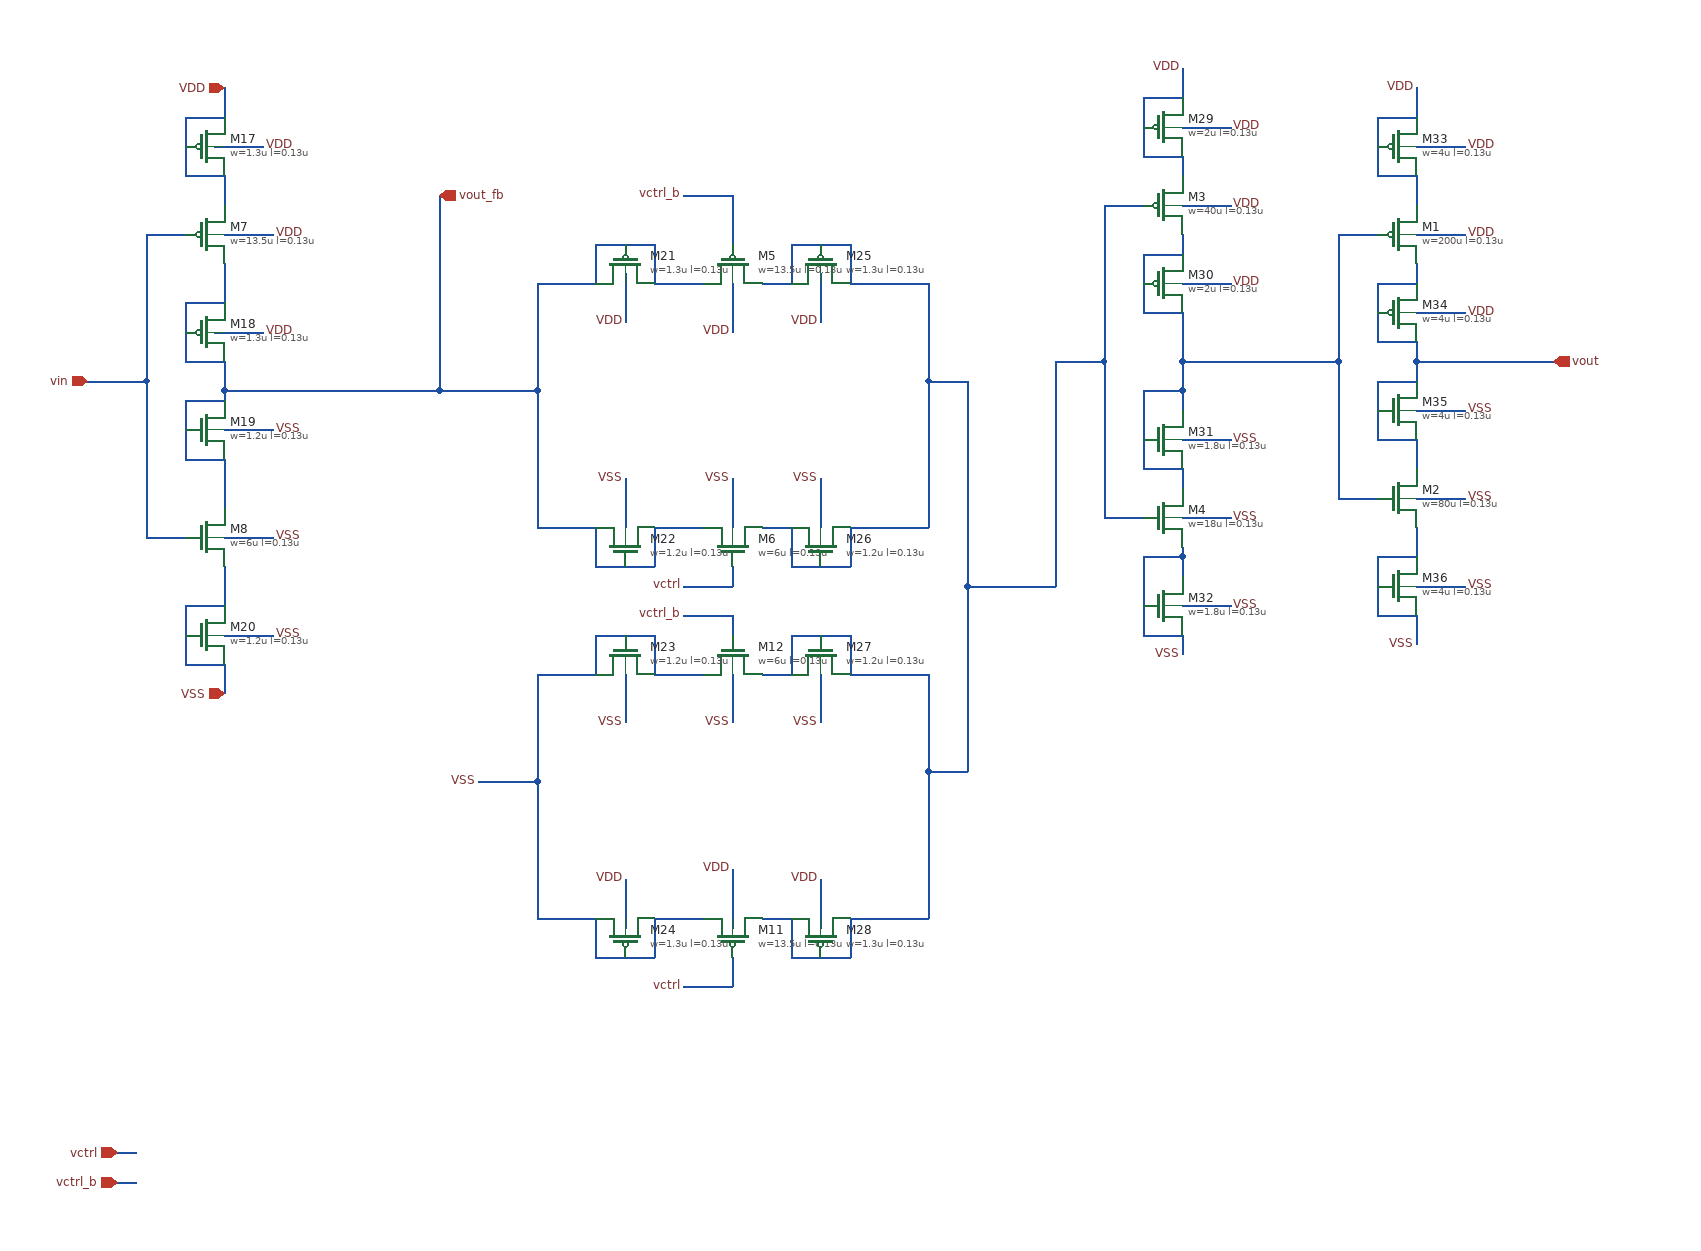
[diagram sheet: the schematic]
v {xschem version=3.4.8RC file_version=1.3}
G {}
K {}
V {}
S {}
F {}
E {}
N 510 -1400 550 -1400 {lab=vin}
N 510 -1090 550 -1090 {lab=vin}
N 590 -1460 590 -1430 {lab=VDD}
N 590 -960 590 -930 {lab=VSS}
N 590 -1400 640 -1400 {lab=VDD}
N 590 -1090 640 -1090 {lab=VSS}
N 510 -1400 510 -1250 {lab=vin}
N 1490 -1430 1530 -1430 {lab=#net1}
N 1490 -1110 1530 -1110 {lab=#net1}
N 1570 -1570 1570 -1540 {lab=VDD}
N 1570 -1070 1570 -1050 {lab=VSS}
N 1570 -1430 1620 -1430 {lab=VDD}
N 1570 -1110 1620 -1110 {lab=VSS}
N 1730 -1400 1770 -1400 {lab=#net2}
N 1730 -1130 1770 -1130 {lab=#net2}
N 1810 -1460 1810 -1430 {lab=VDD}
N 1810 -1100 1810 -1070 {lab=VSS}
N 1810 -1400 1860 -1400 {lab=VDD}
N 1810 -1130 1860 -1130 {lab=VSS}
N 1810 -1270 1810 -1250 {lab=vout}
N 1810 -1270 1950 -1270 {lab=vout}
N 1810 -1290 1810 -1270 {lab=vout}
N 450 -1250 510 -1250 {lab=vin}
N 1570 -1160 1570 -1140 {lab=#net2}
N 1570 -1270 1730 -1270 {lab=#net2}
N 1730 -1270 1730 -1130 {lab=#net2}
N 590 -1370 590 -1330 {lab=vout_fb}
N 1110 -1150 1110 -1100 {lab=VSS}
N 1110 -1350 1110 -1300 {lab=VDD}
N 1110 -1440 1110 -1390 {lab=vctrl_b}
N 1060 -1440 1110 -1440 {lab=vctrl_b}
N 910 -950 970 -950 {lab=VSS}
N 1110 -950 1110 -900 {lab=VSS}
N 1060 -1010 1110 -1010 {lab=vctrl_b}
N 1110 -1010 1110 -990 {lab=vctrl_b}
N 1060 -630 1110 -630 {lab=vctrl}
N 850 -840 910 -840 {lab=VSS}
N 910 -950 910 -840 {lab=VSS}
N 1310 -850 1350 -850 {lab=#net1}
N 1310 -950 1310 -850 {lab=#net1}
N 1350 -1040 1350 -850 {lab=#net1}
N 1310 -1250 1350 -1250 {lab=#net1}
N 1310 -1350 1310 -1250 {lab=#net1}
N 910 -1240 910 -1100 {lab=vout_fb}
N 1350 -1040 1440 -1040 {lab=#net1}
N 1350 -1250 1350 -1040 {lab=#net1}
N 1440 -1270 1440 -1040 {lab=#net1}
N 1440 -1270 1490 -1270 {lab=#net1}
N 810 -1240 910 -1240 {lab=vout_fb}
N 480 -460 500 -460 {lab=vctrl}
N 810 -1440 810 -1240 {lab=vout_fb}
N 580 -1490 630 -1490 {lab=VDD}
N 550 -1460 590 -1460 {lab=VDD}
N 550 -1520 550 -1460 {lab=VDD}
N 550 -1520 590 -1520 {lab=VDD}
N 590 -1550 590 -1520 {lab=VDD}
N 580 -1300 630 -1300 {lab=VDD}
N 550 -1270 590 -1270 {lab=vout_fb}
N 550 -1330 550 -1270 {lab=vout_fb}
N 550 -1330 590 -1330 {lab=vout_fb}
N 550 -1170 590 -1170 {lab=vout_fb}
N 550 -1230 550 -1170 {lab=vout_fb}
N 550 -1230 590 -1230 {lab=vout_fb}
N 590 -1200 640 -1200 {lab=VSS}
N 590 -1240 590 -1230 {lab=vout_fb}
N 550 -960 590 -960 {lab=VSS}
N 550 -1020 550 -960 {lab=VSS}
N 550 -1020 590 -1020 {lab=VSS}
N 590 -990 640 -990 {lab=VSS}
N 590 -1060 590 -1020 {lab=VSS}
N 510 -1250 510 -1090 {lab=vin}
N 590 -1240 810 -1240 {lab=vout_fb}
N 590 -1270 590 -1240 {lab=vout_fb}
N 910 -1350 910 -1240 {lab=vout_fb}
N 1000 -1360 1000 -1310 {lab=VDD}
N 970 -1390 970 -1350 {lab=vout_fb}
N 970 -1390 1030 -1390 {lab=vout_fb}
N 1030 -1390 1030 -1350 {lab=vout_fb}
N 1030 -1350 1080 -1350 {lab=vout_fb}
N 910 -1350 970 -1350 {lab=vout_fb}
N 970 -1100 970 -1060 {lab=vout_fb}
N 970 -1060 1030 -1060 {lab=vout_fb}
N 1030 -1100 1030 -1060 {lab=vout_fb}
N 1060 -1040 1110 -1040 {lab=vctrl}
N 1110 -1060 1110 -1040 {lab=vctrl}
N 1310 -1250 1310 -1100 {lab=#net1}
N 1030 -1100 1080 -1100 {lab=vout_fb}
N 910 -1100 970 -1100 {lab=vout_fb}
N 1000 -1150 1000 -1100 {lab=VSS}
N 970 -990 970 -950 {lab=VSS}
N 970 -990 1030 -990 {lab=VSS}
N 1030 -990 1030 -950 {lab=VSS}
N 1000 -950 1000 -900 {lab=VSS}
N 1030 -950 1080 -950 {lab=VSS}
N 1000 -740 1000 -690 {lab=VDD}
N 1030 -700 1030 -660 {lab=VSS}
N 970 -660 1030 -660 {lab=VSS}
N 970 -700 970 -660 {lab=VSS}
N 1110 -750 1110 -690 {lab=VDD}
N 1310 -850 1310 -700 {lab=#net1}
N 1110 -660 1110 -630 {lab=vctrl}
N 1030 -700 1080 -700 {lab=VSS}
N 910 -840 910 -700 {lab=VSS}
N 910 -700 970 -700 {lab=VSS}
N 1200 -1360 1200 -1310 {lab=VDD}
N 1170 -1390 1170 -1350 {lab=#net1}
N 1170 -1390 1230 -1390 {lab=#net1}
N 1230 -1390 1230 -1350 {lab=#net1}
N 1170 -1100 1170 -1060 {lab=#net1}
N 1170 -1060 1230 -1060 {lab=#net1}
N 1230 -1100 1230 -1060 {lab=#net1}
N 1200 -1150 1200 -1100 {lab=VSS}
N 1140 -1100 1170 -1100 {lab=#net1}
N 1230 -1100 1310 -1100 {lab=#net1}
N 1140 -1350 1170 -1350 {lab=#net1}
N 1230 -1350 1310 -1350 {lab=#net1}
N 1170 -990 1170 -950 {lab=#net1}
N 1170 -990 1230 -990 {lab=#net1}
N 1230 -990 1230 -950 {lab=#net1}
N 1200 -950 1200 -900 {lab=VSS}
N 1140 -950 1170 -950 {lab=#net1}
N 1230 -950 1310 -950 {lab=#net1}
N 1200 -740 1200 -690 {lab=VDD}
N 1230 -700 1230 -660 {lab=#net1}
N 1170 -660 1230 -660 {lab=#net1}
N 1170 -700 1170 -660 {lab=#net1}
N 1140 -700 1170 -700 {lab=#net1}
N 1230 -700 1310 -700 {lab=#net1}
N 1570 -1510 1620 -1510 {lab=VDD}
N 1570 -1480 1570 -1460 {lab=VDD}
N 1530 -1480 1570 -1480 {lab=VDD}
N 1530 -1540 1530 -1480 {lab=VDD}
N 1530 -1540 1570 -1540 {lab=VDD}
N 1570 -1350 1620 -1350 {lab=VDD}
N 1530 -1320 1570 -1320 {lab=#net2}
N 1530 -1380 1530 -1320 {lab=#net2}
N 1530 -1380 1570 -1380 {lab=#net2}
N 1570 -1400 1570 -1380 {lab=#net2}
N 1490 -1430 1490 -1270 {lab=#net1}
N 1570 -1240 1570 -1220 {lab=#net2}
N 1570 -1320 1570 -1270 {lab=#net2}
N 1530 -1240 1570 -1240 {lab=#net2}
N 1570 -1270 1570 -1240 {lab=#net2}
N 1530 -1240 1530 -1160 {lab=#net2}
N 1530 -1160 1570 -1160 {lab=#net2}
N 1570 -1190 1620 -1190 {lab=VSS}
N 1490 -1270 1490 -1110 {lab=#net1}
N 1570 -990 1570 -970 {lab=VSS}
N 1530 -1070 1570 -1070 {lab=VSS}
N 1530 -1070 1530 -990 {lab=VSS}
N 1530 -990 1570 -990 {lab=VSS}
N 1570 -1020 1620 -1020 {lab=VSS}
N 1570 -1080 1570 -1070 {lab=VSS}
N 1810 -1490 1860 -1490 {lab=VDD}
N 1770 -1460 1810 -1460 {lab=VDD}
N 1770 -1520 1770 -1460 {lab=VDD}
N 1770 -1520 1810 -1520 {lab=VDD}
N 1810 -1550 1810 -1520 {lab=VDD}
N 1810 -1320 1860 -1320 {lab=VDD}
N 1770 -1290 1810 -1290 {lab=vout}
N 1770 -1350 1770 -1290 {lab=vout}
N 1770 -1350 1810 -1350 {lab=vout}
N 1810 -1370 1810 -1350 {lab=vout}
N 1730 -1400 1730 -1270 {lab=#net2}
N 1810 -1220 1860 -1220 {lab=VSS}
N 1770 -1190 1810 -1190 {lab=vout}
N 1770 -1250 1770 -1190 {lab=vout}
N 1770 -1250 1810 -1250 {lab=vout}
N 1810 -1190 1810 -1160 {lab=vout}
N 1810 -1040 1860 -1040 {lab=VSS}
N 1770 -1010 1810 -1010 {lab=VSS}
N 1770 -1070 1770 -1010 {lab=VSS}
N 1770 -1070 1810 -1070 {lab=VSS}
N 1810 -1010 1810 -980 {lab=VSS}
N 590 -1170 590 -1120 {lab=vout_fb}
N 480 -430 500 -430 {lab=vctrl}
C {title-3.sym} 0 0 0 0 {name=l1 author="Belal ELshinnawey" rev=1.0 lock=true}
C {devices/iopin.sym} 590 -1550 3 0 {name=p1 lab=VDD}
C {devices/iopin.sym} 590 -930 1 0 {name=p5 lab=VSS}
C {devices/lab_pin.sym} 640 -1400 2 0 {name=lp15 sig_type=std_logic lab=VDD}
C {devices/lab_pin.sym} 640 -1090 2 0 {name=lp16 sig_type=std_logic lab=VSS}
C {sg13cmos5l_pr/sg13_lv_pmos.sym} 570 -1400 0 0 {name=M7
l=0.13u
w=13.5u
ng=10
 m=1
  mm_ok=1
 model=sg13_lv_pmos
spiceprefix=X
}
C {sg13cmos5l_pr/sg13_lv_nmos.sym} 570 -1090 0 0 {name=M8
l=0.13u
w=6u
ng=5
 m=1
  mm_ok=1
 model=sg13_lv_nmos
spiceprefix=X
}
C {ipin.sym} 450 -1250 0 0 {name=p4 lab=vin}
C {devices/lab_pin.sym} 1620 -1430 2 0 {name=lp5 sig_type=std_logic lab=VDD}
C {devices/lab_pin.sym} 1620 -1110 2 0 {name=lp6 sig_type=std_logic lab=VSS}
C {sg13cmos5l_pr/sg13_lv_pmos.sym} 1550 -1430 0 0 {name=M3
l=0.13u
w=40u
ng=20
 m=1
  mm_ok=1
 model=sg13_lv_pmos
spiceprefix=X
}
C {sg13cmos5l_pr/sg13_lv_nmos.sym} 1550 -1110 0 0 {name=M4
l=0.13u
w=18u
ng=10
 m=1
  mm_ok=1
 model=sg13_lv_nmos
spiceprefix=X
}
C {devices/lab_pin.sym} 1570 -970 3 0 {name=lp7 sig_type=std_logic lab=VSS}
C {devices/lab_pin.sym} 1570 -1570 1 0 {name=lp8 sig_type=std_logic lab=VDD}
C {devices/lab_pin.sym} 1860 -1400 2 0 {name=lp1 sig_type=std_logic lab=VDD}
C {devices/lab_pin.sym} 1860 -1130 2 0 {name=lp2 sig_type=std_logic lab=VSS}
C {sg13cmos5l_pr/sg13_lv_pmos.sym} 1790 -1400 0 0 {name=M1
l=0.13u
w=200u
ng=50
 m=1
  mm_ok=1
 model=sg13_lv_pmos
spiceprefix=X
}
C {sg13cmos5l_pr/sg13_lv_nmos.sym} 1790 -1130 0 0 {name=M2
l=0.13u
w=80u
ng=20
 m=1
  mm_ok=1
 model=sg13_lv_nmos
spiceprefix=X
}
C {devices/lab_pin.sym} 1810 -980 3 0 {name=lp3 sig_type=std_logic lab=VSS}
C {devices/lab_pin.sym} 1810 -1550 1 0 {name=lp4 sig_type=std_logic lab=VDD}
C {devices/opin.sym} 1950 -1270 0 0 {name=p2 lab=vout}
C {ipin.sym} 480 -460 0 0 {name=p3 lab=vctrl}
C {sg13cmos5l_pr/sg13_lv_pmos.sym} 1110 -1370 3 1 {name=M5
l=0.13u
w=13.5u
ng=10
 m=1
  mm_ok=1
 model=sg13_lv_pmos
spiceprefix=X
}
C {sg13cmos5l_pr/sg13_lv_nmos.sym} 1110 -1080 1 1 {name=M6
l=0.13u
w=6u
ng=5
 m=1
  mm_ok=1
 model=sg13_lv_nmos
spiceprefix=X
}
C {devices/lab_pin.sym} 1110 -1150 1 0 {name=lp9 sig_type=std_logic lab=VSS}
C {devices/lab_pin.sym} 1110 -1300 3 0 {name=lp10 sig_type=std_logic lab=VDD}
C {devices/lab_pin.sym} 1060 -1440 0 0 {name=lp17 sig_type=std_logic lab=vctrl_b}
C {devices/lab_pin.sym} 1060 -1040 0 0 {name=lp18 sig_type=std_logic lab=vctrl}
C {sg13cmos5l_pr/sg13_lv_pmos.sym} 1110 -680 3 0 {name=M11
l=0.13u
w=13.5u
ng=10
 m=1
  mm_ok=1
 model=sg13_lv_pmos
spiceprefix=X
}
C {sg13cmos5l_pr/sg13_lv_nmos.sym} 1110 -970 1 0 {name=M12
l=0.13u
w=6u
ng=5
 m=1
  mm_ok=1
 model=sg13_lv_nmos
spiceprefix=X
}
C {devices/lab_pin.sym} 1110 -900 3 0 {name=lp20 sig_type=std_logic lab=VSS}
C {devices/lab_pin.sym} 1110 -750 1 0 {name=lp21 sig_type=std_logic lab=VDD}
C {devices/lab_pin.sym} 1060 -1010 2 1 {name=lp23 sig_type=std_logic lab=vctrl_b}
C {devices/lab_pin.sym} 850 -840 0 0 {name=lp24 sig_type=std_logic lab=VSS}
C {devices/lab_pin.sym} 1060 -630 0 0 {name=lp22 sig_type=std_logic lab=vctrl}
C {devices/opin.sym} 810 -1440 3 0 {name=p6 lab=vout_fb}
C {sg13cmos5l_pr/sg13_lv_pmos.sym} 570 -1490 0 0 {name=M17
l=0.13u
w=1.3u
ng=1
 m=1
  mm_ok=1
 model=sg13_lv_pmos
spiceprefix=X
}
C {devices/lab_pin.sym} 630 -1490 2 0 {name=lp29 sig_type=std_logic lab=VDD}
C {sg13cmos5l_pr/sg13_lv_pmos.sym} 570 -1300 0 0 {name=M18
l=0.13u
w=1.3u
ng=1
 m=1
  mm_ok=1
 model=sg13_lv_pmos
spiceprefix=X
}
C {devices/lab_pin.sym} 630 -1300 2 0 {name=lp30 sig_type=std_logic lab=VDD}
C {sg13cmos5l_pr/sg13_lv_nmos.sym} 570 -1200 0 0 {name=M19
l=0.13u
w=1.2u
ng=1
 m=1
  mm_ok=1
 model=sg13_lv_nmos
spiceprefix=X
}
C {devices/lab_pin.sym} 640 -1200 2 0 {name=lp31 sig_type=std_logic lab=VSS}
C {sg13cmos5l_pr/sg13_lv_nmos.sym} 570 -990 0 0 {name=M20
l=0.13u
w=1.2u
ng=1
 m=1
  mm_ok=1
 model=sg13_lv_nmos
spiceprefix=X
}
C {devices/lab_pin.sym} 640 -990 2 0 {name=lp32 sig_type=std_logic lab=VSS}
C {sg13cmos5l_pr/sg13_lv_pmos.sym} 1000 -1370 3 1 {name=M21
l=0.13u
w=1.3u
ng=1
 m=1
  mm_ok=1
 model=sg13_lv_pmos
spiceprefix=X
}
C {devices/lab_pin.sym} 1000 -1310 3 0 {name=lp33 sig_type=std_logic lab=VDD}
C {sg13cmos5l_pr/sg13_lv_nmos.sym} 1000 -1080 1 1 {name=M22
l=0.13u
w=1.2u
ng=1
 m=1
  mm_ok=1
 model=sg13_lv_nmos
spiceprefix=X
}
C {devices/lab_pin.sym} 1000 -1150 3 1 {name=lp34 sig_type=std_logic lab=VSS}
C {sg13cmos5l_pr/sg13_lv_nmos.sym} 1000 -970 1 0 {name=M23
l=0.13u
w=1.2u
ng=1
 m=1
  mm_ok=1
 model=sg13_lv_nmos
spiceprefix=X
}
C {devices/lab_pin.sym} 1000 -900 3 0 {name=lp35 sig_type=std_logic lab=VSS}
C {sg13cmos5l_pr/sg13_lv_pmos.sym} 1000 -680 3 0 {name=M24
l=0.13u
w=1.3u
ng=1
 m=1
  mm_ok=1
 model=sg13_lv_pmos
spiceprefix=X
}
C {devices/lab_pin.sym} 1000 -740 1 0 {name=lp36 sig_type=std_logic lab=VDD}
C {sg13cmos5l_pr/sg13_lv_pmos.sym} 1200 -1370 3 1 {name=M25
l=0.13u
w=1.3u
ng=1
 m=1
  mm_ok=1
 model=sg13_lv_pmos
spiceprefix=X
}
C {devices/lab_pin.sym} 1200 -1310 3 0 {name=lp37 sig_type=std_logic lab=VDD}
C {sg13cmos5l_pr/sg13_lv_nmos.sym} 1200 -1080 1 1 {name=M26
l=0.13u
w=1.2u
ng=1
 m=1
  mm_ok=1
 model=sg13_lv_nmos
spiceprefix=X
}
C {devices/lab_pin.sym} 1200 -1150 3 1 {name=lp38 sig_type=std_logic lab=VSS}
C {sg13cmos5l_pr/sg13_lv_nmos.sym} 1200 -970 1 0 {name=M27
l=0.13u
w=1.2u
ng=1
 m=1
  mm_ok=1
 model=sg13_lv_nmos
spiceprefix=X
}
C {devices/lab_pin.sym} 1200 -900 3 0 {name=lp39 sig_type=std_logic lab=VSS}
C {sg13cmos5l_pr/sg13_lv_pmos.sym} 1200 -680 3 0 {name=M28
l=0.13u
w=1.3u
ng=1
 m=1
  mm_ok=1
 model=sg13_lv_pmos
spiceprefix=X
}
C {devices/lab_pin.sym} 1200 -740 1 0 {name=lp40 sig_type=std_logic lab=VDD}
C {sg13cmos5l_pr/sg13_lv_pmos.sym} 1550 -1510 0 0 {name=M29
l=0.13u
w=2u
ng=1
 m=1
  mm_ok=1
 model=sg13_lv_pmos
spiceprefix=X
}
C {devices/lab_pin.sym} 1620 -1510 2 0 {name=lp41 sig_type=std_logic lab=VDD}
C {sg13cmos5l_pr/sg13_lv_pmos.sym} 1550 -1350 0 0 {name=M30
l=0.13u
w=2u
ng=1
 m=1
  mm_ok=1
 model=sg13_lv_pmos
spiceprefix=X
}
C {devices/lab_pin.sym} 1620 -1350 2 0 {name=lp42 sig_type=std_logic lab=VDD}
C {sg13cmos5l_pr/sg13_lv_nmos.sym} 1550 -1190 0 0 {name=M31
l=0.13u
w=1.8u
ng=1
 m=1
  mm_ok=1
 model=sg13_lv_nmos
spiceprefix=X
}
C {devices/lab_pin.sym} 1620 -1190 2 0 {name=lp43 sig_type=std_logic lab=VSS}
C {sg13cmos5l_pr/sg13_lv_nmos.sym} 1550 -1020 0 0 {name=M32
l=0.13u
w=1.8u
ng=1
 m=1
  mm_ok=1
 model=sg13_lv_nmos
spiceprefix=X
}
C {devices/lab_pin.sym} 1620 -1020 2 0 {name=lp44 sig_type=std_logic lab=VSS}
C {sg13cmos5l_pr/sg13_lv_pmos.sym} 1790 -1490 0 0 {name=M33
l=0.13u
w=4u
ng=1
 m=1
  mm_ok=1
 model=sg13_lv_pmos
spiceprefix=X
}
C {devices/lab_pin.sym} 1860 -1490 2 0 {name=lp45 sig_type=std_logic lab=VDD}
C {sg13cmos5l_pr/sg13_lv_pmos.sym} 1790 -1320 0 0 {name=M34
l=0.13u
w=4u
ng=1
 m=1
  mm_ok=1
 model=sg13_lv_pmos
spiceprefix=X
}
C {devices/lab_pin.sym} 1860 -1320 2 0 {name=lp46 sig_type=std_logic lab=VDD}
C {sg13cmos5l_pr/sg13_lv_nmos.sym} 1790 -1220 0 0 {name=M35
l=0.13u
w=4u
ng=1
 m=1
  mm_ok=1
 model=sg13_lv_nmos
spiceprefix=X
}
C {devices/lab_pin.sym} 1860 -1220 2 0 {name=lp47 sig_type=std_logic lab=VSS}
C {sg13cmos5l_pr/sg13_lv_nmos.sym} 1790 -1040 0 0 {name=M36
l=0.13u
w=4u
ng=1
 m=1
  mm_ok=1
 model=sg13_lv_nmos
spiceprefix=X
}
C {devices/lab_pin.sym} 1860 -1040 2 0 {name=lp48 sig_type=std_logic lab=VSS}
C {ipin.sym} 480 -430 0 0 {name=p7 lab=vctrl_b}
